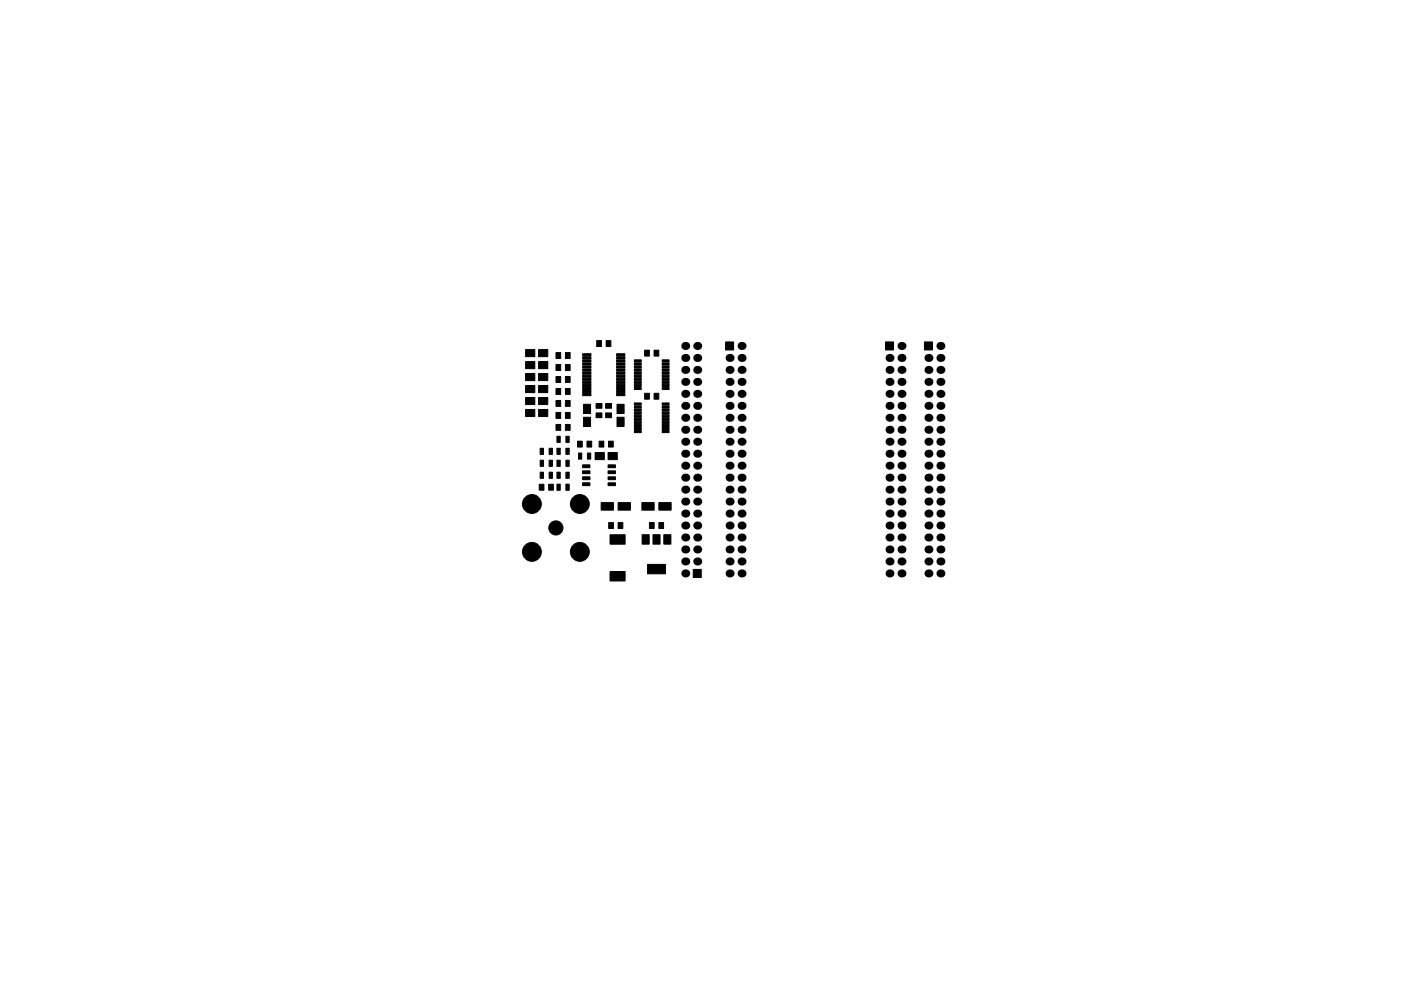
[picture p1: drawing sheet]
<svg xmlns="http://www.w3.org/2000/svg" width="297mm" height="210mm" viewBox="0 0 297 210" stroke-linecap="round" stroke-linejoin="round" font-family="sans-serif">
<g fill="#000" stroke="#000" stroke-width=".21">
<path d="M111.4 79.3h2v1.5h-2zM111.4 76.7h2v1.5h-2zM111.4 74.2h2v1.5h-2zM114.2 79.3h1.9v1.5h-1.9zM114.2 76.7h1.9v1.5h-1.9zM114.2 74.2h1.9v1.5h-1.9zM117.9 79.9h1v1.2h-1zM117.9 77.3h1v1.3h-1zM117.9 74.8h1v1.3h-1zM119.9 79.9h1v1.2h-1zM119.9 77.3h1v1.3h-1zM119.9 74.8h1v1.3h-1z"/>
<path d="M123.5 75h1.8v.5h-1.8zM123.5 75.7h1.8v.4h-1.8zM123.5 76.3h1.8v.5h-1.8zM123.5 77h1.8v.4h-1.8zM123.5 77.6h1.8v.5h-1.8zM123.5 78.3h1.8v.4h-1.8zM123.5 78.9h1.8v.5h-1.8zM123.5 79.6h1.8v.4h-1.8zM126.5 72.3h1v1.2h-1zM128.5 72.3h1v1.2h-1zM130.7 79.6h1.8v.4h-1.8zM130.7 78.9h1.8v.5h-1.8z"/>
<path d="M130.7 78.3h1.8v.4h-1.8zM130.7 77.6h1.8v.5h-1.8zM130.7 77h1.8v.4h-1.8zM130.7 76.3h1.8v.5h-1.8zM130.7 75.7h1.8v.4h-1.8zM130.7 75h1.8v.5h-1.8zM134.5 76.3h1.5v.5h-1.5zM134.5 77h1.5v.4h-1.5zM134.5 77.6h1.5v.5h-1.5zM134.5 78.3h1.5v.4h-1.5zM134.5 78.9h1.5v.5h-1.5zM136.7 74.3h1v1.2h-1z"/>
<path d="M138.7 74.3h1v1.2h-1zM140.4 78.9h1.5v.5h-1.5zM140.4 78.3h1.5v.4h-1.5zM140.4 77.6h1.5v.5h-1.5zM140.4 77h1.5v.4h-1.5zM140.4 76.3h1.5v.5h-1.5zM153.8 72.6h1.7v1.7h-1.7zM187.7 72.6h1.7v1.7h-1.7zM196 72.6h1.7v1.7h-1.7zM111.4 86.9h2v1.5h-2zM111.4 81.8h2v1.5h-2zM111.4 84.3h2v1.5h-2z"/>
<path d="M114.5 97.6h.7v1.3h-.7zM114.5 95.1h.7v1.3h-.7zM114.2 86.9h1.9v1.5h-1.9zM114.2 81.8h1.9v1.5h-1.9zM114.2 84.3h1.9v1.5h-1.9zM116.4 97.6h.7v1.3h-.7zM116.4 95.1h.7v1.3h-.7zM118.1 97.6h.7v1.3h-.7zM118.1 95.1h.7v1.3h-.7zM118.1 92.6h.7v1.3h-.7zM117.9 87.5h1v1.3h-1zM117.9 82.4h1v1.3h-1z"/>
<path d="M117.9 90h1v1.3h-1zM117.9 85h1v1.2h-1zM120 97.6h.7v1.3h-.7zM120 95.1h.7v1.3h-.7zM120 92.6h.7v1.3h-.7zM119.9 87.5h1v1.3h-1zM119.9 82.4h1v1.3h-1zM119.9 90h1v1.3h-1zM119.9 85h1v1.2h-1zM122.7 96.1h.7v1.3h-.7zM122.5 93.6h1v1.3h-1zM123.5 98.6h1.6v.6h-1.6z"/>
<path d="M123.7 85.8h1.5v1.9h-1.5zM123.7 88.5h1.5v2h-1.5zM124.6 96.1h.7v1.3h-.7zM123.5 80.2h1.8v.5h-1.8zM123.5 80.9h1.8v.4h-1.8zM123.5 81.5h1.8v.5h-1.8zM123.5 82.2h1.8v.4h-1.8zM123.5 82.8h1.8v.5h-1.8zM123.5 83.5h1.8v.4h-1.8zM124.5 93.6h1v1.3h-1zM126.4 85.6h1.2v1h-1.2zM126.4 87.6h1.2v1h-1.2z"/>
<path d="M127 93.6h1v1.3h-1zM126.2 96h1.9v1.5h-1.9zM128.4 85.6h1.3v1h-1.3zM128.4 87.6h1.3v1h-1.3zM128.9 98.6h1.6v.6h-1.6zM129 93.6h1v1.3h-1zM130.8 85.8h1.5v1.9h-1.5zM130.8 88.5h1.5v2h-1.5zM128.9 96h2v1.5h-2zM130.7 83.5h1.8v.4h-1.8zM130.7 82.8h1.8v.5h-1.8zM130.7 82.2h1.8v.4h-1.8z"/>
<path d="M130.7 81.5h1.8v.5h-1.8zM130.7 80.9h1.8v.4h-1.8zM130.7 80.2h1.8v.5h-1.8zM134.5 79.6h1.5v.4h-1.5zM134.5 80.2h1.5v.5h-1.5zM134.5 80.9h1.5v.4h-1.5zM134.5 81.5h1.5v.5h-1.5zM134.5 82.2h1.5v.4h-1.5zM134.5 85.5h1.5v.4h-1.5zM134.5 86.1h1.5v.5h-1.5zM134.5 86.8h1.5v.4h-1.5zM134.5 87.4h1.5v.5h-1.5z"/>
<path d="M134.5 88.1h1.5v.4h-1.5zM134.5 88.7h1.5v.5h-1.5zM134.5 89.4h1.5v.4h-1.5zM134.5 90h1.5v.5h-1.5zM134.5 90.7h1.5v.4h-1.5zM134.5 91.3h1.5v.5h-1.5zM136.7 83.4h1v1.3h-1zM138.7 83.4h1v1.3h-1zM140.4 82.2h1.5v.4h-1.5zM140.4 81.5h1.5v.5h-1.5zM140.4 80.9h1.5v.4h-1.5zM140.4 80.2h1.5v.5h-1.5z"/>
<path d="M140.4 79.6h1.5v.4h-1.5zM140.4 91.3h1.5v.5h-1.5zM140.4 90.7h1.5v.4h-1.5zM140.4 90h1.5v.5h-1.5zM140.4 89.4h1.5v.4h-1.5zM140.4 88.7h1.5v.5h-1.5zM140.4 88.1h1.5v.4h-1.5zM140.4 87.4h1.5v.5h-1.5zM140.4 86.8h1.5v.4h-1.5zM140.4 86.1h1.5v.5h-1.5zM140.4 85.5h1.5v.4h-1.5zM114.5 100.2h.7v1.3h-.7z"/>
<path d="M114.3 102.7h1v1.3h-1zM116.4 100.2h.7v1.3h-.7zM116.3 102.7h1v1.3h-1zM118.1 102.7h.7v1.3h-.7zM118.1 100.2h.7v1.3h-.7zM120 102.7h.7v1.3h-.7zM120 100.2h.7v1.3h-.7zM123.5 99.9h1.6v.6h-1.6zM123.5 101.2h1.6v.6h-1.6zM123.5 102.4h1.6v.6h-1.6zM128.9 102.4h1.6v.6h-1.6zM128.9 101.2h1.6v.6h-1.6z"/>
<path d="M128.9 99.9h1.6v.6h-1.6zM129.1 110.9h1v1.2h-1zM129.3 113.5h3.2v2h-3.2zM127.5 106.6h2.6v1.6h-2.6zM131.1 110.9h1v1.2h-1zM131.1 106.6h2.6v1.6h-2.6zM136.1 113.4h1.5v2h-1.5zM137.3 119.7h3.8v2h-3.8zM137.7 110.9h1v1.2h-1zM138.4 113.4h1.5v2h-1.5zM136.1 106.6h2.6v1.6h-2.6zM139.7 110.9h1v1.2h-1z"/>
<path d="M140.7 113.4h1.5v2h-1.5zM139.7 106.6h2.6v1.6h-2.6zM129.3 121.3h3.2v2h-3.2zM147 120.8h1.7v1.7h-1.7z"/>
<circle cx="112.8" cy="106.9" r="2"/>
<circle cx="112.8" cy="117.1" r="2"/>
<circle cx="117.9" cy="112" r="1.5"/>
<circle cx="122.9" cy="117.1" r="2"/>
<circle cx="122.9" cy="106.9" r="2"/>
</g>
<g fill="#000">
<circle cx="145.3" cy="78.5" r=".85"/>
<circle cx="145.3" cy="75.9" r=".85"/>
<circle cx="145.3" cy="73.4" r=".85"/>
<circle cx="147.8" cy="78.5" r=".85"/>
<circle cx="147.8" cy="73.4" r=".85"/>
<circle cx="147.8" cy="75.9" r=".85"/>
<circle cx="154.7" cy="78.5" r=".85"/>
<circle cx="154.7" cy="75.9" r=".85"/>
<circle cx="157.2" cy="78.5" r=".85"/>
<circle cx="157.2" cy="73.4" r=".85"/>
<circle cx="157.2" cy="75.9" r=".85"/>
<circle cx="188.6" cy="78.5" r=".85"/>
<circle cx="188.6" cy="75.9" r=".85"/>
<circle cx="191.1" cy="78.5" r=".85"/>
<circle cx="191.1" cy="73.4" r=".85"/>
<circle cx="191.1" cy="75.9" r=".85"/>
<circle cx="196.8" cy="78.5" r=".85"/>
<circle cx="196.8" cy="75.9" r=".85"/>
<circle cx="199.4" cy="73.4" r=".85"/>
<circle cx="199.4" cy="78.5" r=".85"/>
<circle cx="199.4" cy="75.9" r=".85"/>
<circle cx="145.3" cy="96.3" r=".85"/>
<circle cx="145.3" cy="88.6" r=".85"/>
<circle cx="145.3" cy="83.6" r=".85"/>
<circle cx="145.3" cy="81" r=".85"/>
<circle cx="145.3" cy="93.7" r=".85"/>
<circle cx="145.3" cy="86.1" r=".85"/>
<circle cx="145.3" cy="98.8" r=".85"/>
<circle cx="145.3" cy="91.2" r=".85"/>
<circle cx="147.8" cy="93.7" r=".85"/>
<circle cx="147.8" cy="88.6" r=".85"/>
<circle cx="147.8" cy="86.1" r=".85"/>
<circle cx="147.8" cy="96.3" r=".85"/>
<circle cx="147.8" cy="91.2" r=".85"/>
<circle cx="147.8" cy="81" r=".85"/>
<circle cx="147.8" cy="98.8" r=".85"/>
<circle cx="147.8" cy="83.6" r=".85"/>
<circle cx="154.7" cy="93.7" r=".85"/>
<circle cx="154.7" cy="96.3" r=".85"/>
<circle cx="154.7" cy="81" r=".85"/>
<circle cx="154.7" cy="86.1" r=".85"/>
<circle cx="154.7" cy="83.6" r=".85"/>
<circle cx="154.7" cy="91.2" r=".85"/>
<circle cx="154.7" cy="98.8" r=".85"/>
<circle cx="154.7" cy="88.6" r=".85"/>
<circle cx="157.2" cy="96.3" r=".85"/>
<circle cx="157.2" cy="93.7" r=".85"/>
<circle cx="157.2" cy="86.1" r=".85"/>
<circle cx="157.2" cy="81" r=".85"/>
<circle cx="157.2" cy="83.6" r=".85"/>
<circle cx="157.2" cy="88.6" r=".85"/>
<circle cx="157.2" cy="91.2" r=".85"/>
<circle cx="157.2" cy="98.8" r=".85"/>
<circle cx="188.6" cy="96.3" r=".85"/>
<circle cx="188.6" cy="88.6" r=".85"/>
<circle cx="188.6" cy="86.1" r=".85"/>
<circle cx="188.6" cy="93.7" r=".85"/>
<circle cx="188.6" cy="83.6" r=".85"/>
<circle cx="188.6" cy="91.2" r=".85"/>
<circle cx="188.6" cy="81" r=".85"/>
<circle cx="188.6" cy="98.8" r=".85"/>
<circle cx="191.1" cy="86.1" r=".85"/>
<circle cx="191.1" cy="83.6" r=".85"/>
<circle cx="191.1" cy="88.6" r=".85"/>
<circle cx="191.1" cy="91.2" r=".85"/>
<circle cx="191.1" cy="93.7" r=".85"/>
<circle cx="191.1" cy="96.3" r=".85"/>
<circle cx="191.1" cy="81" r=".85"/>
<circle cx="191.1" cy="98.8" r=".85"/>
<circle cx="196.8" cy="91.2" r=".85"/>
<circle cx="196.8" cy="86.1" r=".85"/>
<circle cx="196.8" cy="88.6" r=".85"/>
<circle cx="196.8" cy="93.7" r=".85"/>
<circle cx="196.8" cy="81" r=".85"/>
<circle cx="196.8" cy="83.6" r=".85"/>
<circle cx="196.8" cy="96.3" r=".85"/>
<circle cx="196.8" cy="98.8" r=".85"/>
<circle cx="199.4" cy="88.6" r=".85"/>
<circle cx="199.4" cy="83.6" r=".85"/>
<circle cx="199.4" cy="86.1" r=".85"/>
<circle cx="199.4" cy="91.2" r=".85"/>
<circle cx="199.4" cy="93.7" r=".85"/>
<circle cx="199.4" cy="96.3" r=".85"/>
<circle cx="199.4" cy="81" r=".85"/>
<circle cx="199.4" cy="98.8" r=".85"/>
<circle cx="145.3" cy="114" r=".85"/>
<circle cx="145.3" cy="119.1" r=".85"/>
<circle cx="145.3" cy="116.6" r=".85"/>
<circle cx="145.3" cy="109" r=".85"/>
<circle cx="145.3" cy="101.3" r=".85"/>
<circle cx="145.3" cy="111.5" r=".85"/>
<circle cx="145.3" cy="103.9" r=".85"/>
<circle cx="145.3" cy="106.4" r=".85"/>
<circle cx="147.8" cy="109" r=".85"/>
<circle cx="147.8" cy="116.6" r=".85"/>
<circle cx="147.8" cy="103.9" r=".85"/>
<circle cx="147.8" cy="119.1" r=".85"/>
<circle cx="147.8" cy="114" r=".85"/>
<circle cx="147.8" cy="111.5" r=".85"/>
<circle cx="147.8" cy="101.3" r=".85"/>
<circle cx="147.8" cy="106.4" r=".85"/>
<circle cx="154.7" cy="103.9" r=".85"/>
<circle cx="154.7" cy="109" r=".85"/>
<circle cx="154.7" cy="116.6" r=".85"/>
<circle cx="154.7" cy="119.1" r=".85"/>
<circle cx="154.7" cy="111.5" r=".85"/>
<circle cx="154.7" cy="114" r=".85"/>
<circle cx="154.7" cy="101.3" r=".85"/>
<circle cx="154.7" cy="106.4" r=".85"/>
<circle cx="157.2" cy="114" r=".85"/>
<circle cx="157.2" cy="119.1" r=".85"/>
<circle cx="157.2" cy="106.4" r=".85"/>
<circle cx="157.2" cy="111.5" r=".85"/>
<circle cx="157.2" cy="116.6" r=".85"/>
<circle cx="157.2" cy="101.3" r=".85"/>
<circle cx="157.2" cy="109" r=".85"/>
<circle cx="157.2" cy="103.9" r=".85"/>
<circle cx="188.6" cy="109" r=".85"/>
<circle cx="188.6" cy="116.6" r=".85"/>
<circle cx="188.6" cy="101.3" r=".85"/>
<circle cx="188.6" cy="103.9" r=".85"/>
<circle cx="188.6" cy="106.4" r=".85"/>
<circle cx="188.6" cy="111.5" r=".85"/>
<circle cx="188.6" cy="119.1" r=".85"/>
<circle cx="188.6" cy="114" r=".85"/>
<circle cx="191.1" cy="111.5" r=".85"/>
<circle cx="191.1" cy="109" r=".85"/>
<circle cx="191.1" cy="116.6" r=".85"/>
<circle cx="191.1" cy="101.3" r=".85"/>
<circle cx="191.1" cy="103.9" r=".85"/>
<circle cx="191.1" cy="106.4" r=".85"/>
<circle cx="191.1" cy="119.1" r=".85"/>
<circle cx="191.1" cy="114" r=".85"/>
<circle cx="196.8" cy="101.3" r=".85"/>
<circle cx="196.8" cy="109" r=".85"/>
<circle cx="196.8" cy="116.6" r=".85"/>
<circle cx="196.8" cy="103.9" r=".85"/>
<circle cx="196.8" cy="106.4" r=".85"/>
<circle cx="196.8" cy="111.5" r=".85"/>
<circle cx="196.8" cy="119.1" r=".85"/>
<circle cx="196.8" cy="114" r=".85"/>
<circle cx="199.4" cy="116.6" r=".85"/>
<circle cx="199.4" cy="101.3" r=".85"/>
<circle cx="199.4" cy="103.9" r=".85"/>
<circle cx="199.4" cy="106.4" r=".85"/>
<circle cx="199.4" cy="109" r=".85"/>
<circle cx="199.4" cy="114" r=".85"/>
<circle cx="199.4" cy="111.5" r=".85"/>
<circle cx="199.4" cy="119.1" r=".85"/>
<circle cx="145.3" cy="121.7" r=".85"/>
<circle cx="154.7" cy="121.7" r=".85"/>
<circle cx="157.2" cy="121.7" r=".85"/>
<circle cx="188.6" cy="121.7" r=".85"/>
<circle cx="191.1" cy="121.7" r=".85"/>
<circle cx="196.8" cy="121.7" r=".85"/>
<circle cx="199.4" cy="121.7" r=".85"/>
</g>
</svg>
